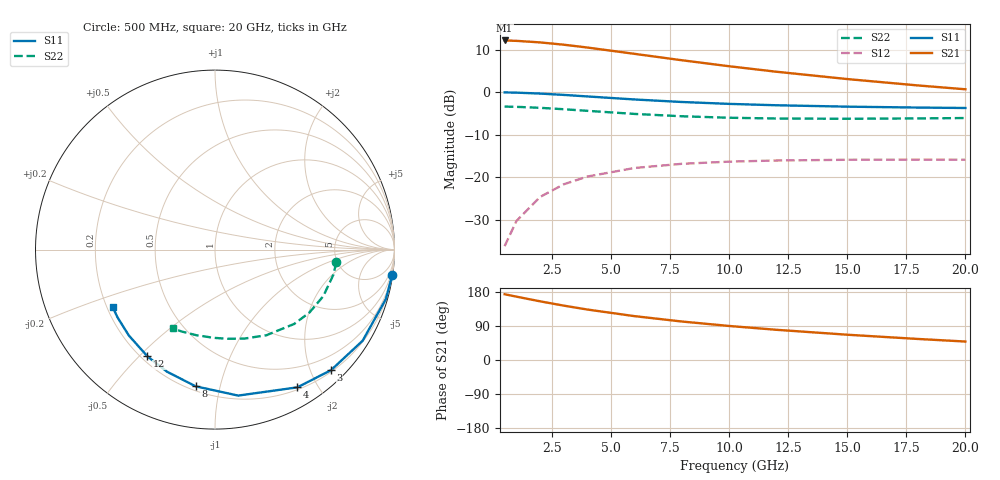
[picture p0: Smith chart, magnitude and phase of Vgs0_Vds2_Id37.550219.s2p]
# Hz S RI R 50
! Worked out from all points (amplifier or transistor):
!   12 points, 500 MHz to 20 GHz, reference 50 ohm
!   highest |S21| = 12.2 dB at 500 MHz (marker M1)
!   |S21| within 3 dB of that: start of sweep to 5.793 GHz
!   unconditionally stable (mu >= 1): 18.29 GHz to end of sweep
!   at 2 GHz: K = 0.10, MSG = 18.2 dB, |S12| = -24.6 dB
!   at 8 GHz: K = 0.42, MSG = 12.2 dB, |S12| = -16.8 dB
!   at 20 GHz: K = 1.10, MAG = 6.3 dB, |S12| = -15.9 dB
!   S11 on the Smith chart (normalised r, x): 500 MHz: 0, -14; 3 GHz: 0.23, -2.33; 4 GHz: 0.23, -1.74; 8 GHz: 0.23, -0.84; 12 GHz: 0.22, -0.53; 20 GHz: 0.22, -0.25
5e8  0.9877 -0.1411  -4.052 0.4579  0.00149 0.0154  0.6757 -0.0707
1e9  0.9518 -0.276  -3.933 0.8954  0.00583 0.03  0.6601 -0.1389
2e9  0.8223 -0.5078  -3.503 1.643  0.0214 0.0545  0.6035 -0.2592
3e9  0.6466 -0.6716  -2.922 2.162  0.0425 0.0708  0.526 -0.3508
4e9  0.459 -0.7675  -2.304 2.455  0.0648 0.0787  0.4417 -0.4139
6e9  0.1291 -0.8134  -1.23 2.555  0.1032 0.0768  0.2869 -0.477
8e9  -0.108 -0.7616  -0.4778 2.337  0.1293 0.0634  0.1646 -0.4958
1e10  -0.2681 -0.6798  0.00665 2.027  0.1453 0.047  0.0695 -0.497
1.2e10  -0.3765 -0.5949  0.3117 1.719  0.1544 0.031  -0.00804 -0.4914
1.5e10  -0.4802 -0.4783  0.5661 1.315  0.1604 0.00969  -0.1044 -0.4769
1.8e10  -0.5429 -0.3779  0.6823 0.992  0.1611 -0.00788  -0.186 -0.4563
2e10  -0.5708 -0.3187  0.7162 0.8158  0.1601 -0.0178  -0.2344 -0.4393
